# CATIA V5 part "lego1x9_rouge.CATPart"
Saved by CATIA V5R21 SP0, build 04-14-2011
Part number: lego1x9_rouge
Definition: Brique LEGO® 1x9, couleur Rouge
Description: Brique LEGO® 1x9, couleur Rouge
Property "SUPPLIER": "LEGO®"
Property "SUPPLIER": "LEGO®"
Property "DESIGN": "Brique LEGO® 1x9, couleur Rouge"
Property "DESIGN": "Brique LEGO® 1x9, couleur Rouge"
Property "TraceParts.PartNumber": "10-20122010-074223"
Property "TRACEPARTS": "TRACEPARTS"
Property "TraceParts.PartTitle": "Brique LEGO® 1x9"
Property "TraceParts.InstanceId": "10-20122010-07422310UFQ9W313DGN2O2A8ITDW7CR"
Property "TraceParts.PartVersion": "1.0.7"
Property "TraceParts.PartLanguage": "fr"
Bounding box of the stored display mesh (mm): x -4 to 68, y 0 to 11.2, z -4 to 4
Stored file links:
  C:\TPO v2\SharedFS\Outgoing\lego1x9_rouge.CATPart

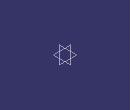
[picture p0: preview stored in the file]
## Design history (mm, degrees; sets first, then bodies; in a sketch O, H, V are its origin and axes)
AxisSystem1: origin (0, 0, 0), X (1, 0, 0), Y (0, 1, 0), Z (0, 0, 1)
Body1 "lego1x9_rouge" (main body)
  Solid1: solid without history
